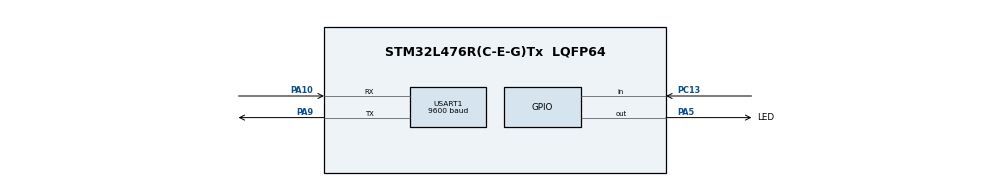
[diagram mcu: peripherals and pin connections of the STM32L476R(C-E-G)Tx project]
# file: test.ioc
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Mcu.Family=STM32L4
Mcu.Name=STM32L476R(C-E-G)Tx
Mcu.Package=LQFP64
NVIC.PriorityGroup=NVIC_PRIORITYGROUP_4
PA10.Mode=Asynchronous
PA10.Signal=USART1_RX
PA5.GPIO_Label=LED
PA5.Signal=GPIO_Output
PA9.Mode=Asynchronous
PA9.Signal=USART1_TX
PC13.Signal=GPIO_Input
ProjectManager.HeapSize=0x200
ProjectManager.StackSize=0x400
ProjectManager.TargetToolchain=STM32CubeIDE
RCC.AHBFreq_Value=80000000
RCC.APB1Freq_Value=80000000
RCC.APB1TimCLKDivider=2
RCC.APB1TimFreq_Value=160000000
RCC.APB2Freq_Value=80000000
RCC.APB2TimFreq_Value=80000000
RCC.CortexFreq_Value=80000000
RCC.HCLKFreq_Value=80000000
RCC.HSE_VALUE=8000000
RCC.HSI_VALUE=16000000
RCC.LSE_VALUE=32768
RCC.MSI_VALUE=4000000
RCC.SYSCLKFreq_VALUE=80000000
RCC.SYSCLKSource=RCC_SYSCLKSOURCE_PLLCLK
RCC.VCOOutputFreq_Value=160000000
USART1.BaudRate=9600
USART1.VirtualMode-Asynchronous=VM_ASYNC
board=custom

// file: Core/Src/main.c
/* USER CODE BEGIN Header */
/**
  ******************************************************************************
  * @file           : main.c
  * @brief          : Main program body
  ******************************************************************************
  * @attention
  *
  * Copyright (c) 2024 STMicroelectronics.
  * All rights reserved.
  *
  * This software is licensed under terms that can be found in the LICENSE file
  * in the root directory of this software component.
  * If no LICENSE file comes with this software, it is provided AS-IS.
  *
  ******************************************************************************
  */
/* USER CODE END Header */
#include "main.h"

UART_HandleTypeDef huart1;

void SystemClock_Config(void);
static void MX_GPIO_Init(void);
static void MX_USART1_UART_Init(void);

int main(void)
{

  /* MCU Configuration--------------------------------------------------------*/

  /* Reset of all peripherals, Initializes the Flash interface and the Systick. */
  HAL_Init();

  /* Configure the system clock */
  SystemClock_Config();

  /* Initialize all configured peripherals */
  MX_GPIO_Init();
  MX_USART1_UART_Init();

  /* Infinite loop */
  while (1)
  {

    /* USER CODE BEGIN 3 */

    if (HAL_GPIO_ReadPin(GPIOC, GPIO_PIN_13)){

    	HAL_GPIO_TogglePin(LED_GPIO_Port, LED_Pin);
    }

  }
  /* USER CODE END 3 */
}

void SystemClock_Config(void)
{
  RCC_OscInitTypeDef RCC_OscInitStruct = {0};
  RCC_ClkInitTypeDef RCC_ClkInitStruct = {0};

  /** Configure the main internal regulator output voltage
  */
  if (HAL_PWREx_ControlVoltageScaling(PWR_REGULATOR_VOLTAGE_SCALE1) != HAL_OK)
  {
    Error_Handler();
  }

  /** Initializes the RCC Oscillators according to the specified parameters
  * in the RCC_OscInitTypeDef structure.
  */
  RCC_OscInitStruct.OscillatorType = RCC_OSCILLATORTYPE_MSI;
  RCC_OscInitStruct.MSIState = RCC_MSI_ON;
  RCC_OscInitStruct.MSICalibrationValue = 0;
  RCC_OscInitStruct.MSIClockRange = RCC_MSIRANGE_6;
  RCC_OscInitStruct.PLL.PLLState = RCC_PLL_ON;
  RCC_OscInitStruct.PLL.PLLSource = RCC_PLLSOURCE_MSI;
  RCC_OscInitStruct.PLL.PLLM = 1;
  RCC_OscInitStruct.PLL.PLLN = 8;
  RCC_OscInitStruct.PLL.PLLP = RCC_PLLP_DIV7;
  RCC_OscInitStruct.PLL.PLLQ = RCC_PLLQ_DIV2;
  RCC_OscInitStruct.PLL.PLLR = RCC_PLLR_DIV2;
  if (HAL_RCC_OscConfig(&RCC_OscInitStruct) != HAL_OK)
  {
    Error_Handler();
  }

  /** Initializes the CPU, AHB and APB buses clocks
  */
  RCC_ClkInitStruct.ClockType = RCC_CLOCKTYPE_HCLK|RCC_CLOCKTYPE_SYSCLK
                              |RCC_CLOCKTYPE_PCLK1|RCC_CLOCKTYPE_PCLK2;
  RCC_ClkInitStruct.SYSCLKSource = RCC_SYSCLKSOURCE_PLLCLK;
  RCC_ClkInitStruct.AHBCLKDivider = RCC_SYSCLK_DIV1;
  RCC_ClkInitStruct.APB1CLKDivider = RCC_HCLK_DIV1;
  RCC_ClkInitStruct.APB2CLKDivider = RCC_HCLK_DIV1;

  if (HAL_RCC_ClockConfig(&RCC_ClkInitStruct, FLASH_LATENCY_4) != HAL_OK)
  {
    Error_Handler();
  }
}

static void MX_USART1_UART_Init(void)
{

  huart1.Instance = USART1;
  huart1.Init.BaudRate = 115200;
  huart1.Init.WordLength = UART_WORDLENGTH_8B;
  huart1.Init.StopBits = UART_STOPBITS_1;
  huart1.Init.Parity = UART_PARITY_NONE;
  huart1.Init.Mode = UART_MODE_TX_RX;
  huart1.Init.HwFlowCtl = UART_HWCONTROL_NONE;
  huart1.Init.OverSampling = UART_OVERSAMPLING_16;
  huart1.Init.OneBitSampling = UART_ONE_BIT_SAMPLE_DISABLE;
  huart1.AdvancedInit.AdvFeatureInit = UART_ADVFEATURE_NO_INIT;
  if (HAL_UART_Init(&huart1) != HAL_OK)
  {
    Error_Handler();
  }

}

static void MX_GPIO_Init(void)
{
  GPIO_InitTypeDef GPIO_InitStruct = {0};

  /* GPIO Ports Clock Enable */
  __HAL_RCC_GPIOC_CLK_ENABLE();
  __HAL_RCC_GPIOA_CLK_ENABLE();

  /*Configure GPIO pin Output Level */
  HAL_GPIO_WritePin(LED_GPIO_Port, LED_Pin, GPIO_PIN_RESET);

  /*Configure GPIO pin : PC13 */
  GPIO_InitStruct.Pin = GPIO_PIN_13;
  GPIO_InitStruct.Mode = GPIO_MODE_INPUT;
  GPIO_InitStruct.Pull = GPIO_PULLDOWN;
  HAL_GPIO_Init(GPIOC, &GPIO_InitStruct);

  /*Configure GPIO pin : LED_Pin */
  GPIO_InitStruct.Pin = LED_Pin;
  GPIO_InitStruct.Mode = GPIO_MODE_OUTPUT_PP;
  GPIO_InitStruct.Pull = GPIO_NOPULL;
  GPIO_InitStruct.Speed = GPIO_SPEED_FREQ_LOW;
  HAL_GPIO_Init(LED_GPIO_Port, &GPIO_InitStruct);

}

void Error_Handler(void)
{
  __disable_irq();
  while (1)
  {
  }
}
